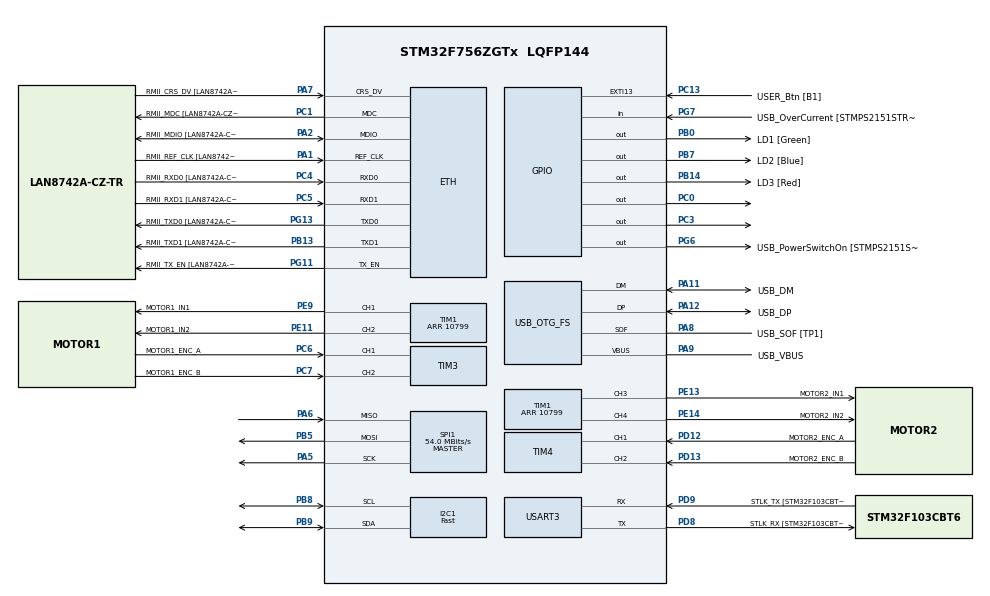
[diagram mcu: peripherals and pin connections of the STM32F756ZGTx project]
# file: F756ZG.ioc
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Dma.I2C1_RX.0.Direction=DMA_PERIPH_TO_MEMORY
Dma.I2C1_RX.0.FIFOMode=DMA_FIFOMODE_DISABLE
Dma.I2C1_RX.0.Instance=DMA1_Stream0
Dma.I2C1_RX.0.MemDataAlignment=DMA_MDATAALIGN_BYTE
Dma.I2C1_RX.0.MemInc=DMA_MINC_ENABLE
Dma.I2C1_RX.0.Mode=DMA_CIRCULAR
Dma.I2C1_RX.0.PeriphDataAlignment=DMA_PDATAALIGN_BYTE
Dma.I2C1_RX.0.PeriphInc=DMA_PINC_DISABLE
Dma.I2C1_RX.0.Priority=DMA_PRIORITY_LOW
Dma.I2C1_TX.1.Direction=DMA_MEMORY_TO_PERIPH
Dma.I2C1_TX.1.FIFOMode=DMA_FIFOMODE_DISABLE
Dma.I2C1_TX.1.Instance=DMA1_Stream6
Dma.I2C1_TX.1.MemDataAlignment=DMA_MDATAALIGN_BYTE
Dma.I2C1_TX.1.MemInc=DMA_MINC_ENABLE
Dma.I2C1_TX.1.Mode=DMA_CIRCULAR
Dma.I2C1_TX.1.PeriphDataAlignment=DMA_PDATAALIGN_BYTE
Dma.I2C1_TX.1.PeriphInc=DMA_PINC_DISABLE
Dma.I2C1_TX.1.Priority=DMA_PRIORITY_LOW
Dma.Request0=I2C1_RX
Dma.Request1=I2C1_TX
ETH.MediaInterface=HAL_ETH_RMII_MODE
ETH.PHY_Name=LAN8742A_PHY_ADDRESS
ETH.PHY_Value=0
ETH.PhyAddress=0
I2C1.Analog_Filter=I2C_ANALOGFILTER_ENABLE
I2C1.I2C_Rise_Time=0
I2C1.I2C_Speed_Mode=I2C_Fast
I2C1.Timing=0x6000030D
Mcu.Family=STM32F7
Mcu.Name=STM32F756ZGTx
Mcu.Package=LQFP144
NVIC.DMA1_Stream0_IRQn=true\:0\:0\:false\:false\:true\:false\:true\:true
NVIC.DMA1_Stream6_IRQn=true\:0\:0\:false\:false\:true\:false\:true\:true
NVIC.I2C1_ER_IRQn=true\:0\:0\:false\:false\:true\:true\:true\:true
NVIC.I2C1_EV_IRQn=true\:0\:0\:false\:false\:true\:true\:true\:true
NVIC.PriorityGroup=NVIC_PRIORITYGROUP_4
PA1.GPIO_Label=RMII_REF_CLK [LAN8742A-CZ-TR_REFCLK0]
PA1.Mode=RMII
PA1.Signal=ETH_REF_CLK
PA10.GPIO_Label=USB_ID
PA10.Signal=USB_OTG_FS_ID
PA11.GPIO_Label=USB_DM
PA11.Mode=Device_Only
PA11.Signal=USB_OTG_FS_DM
PA12.GPIO_Label=USB_DP
PA12.Mode=Device_Only
PA12.Signal=USB_OTG_FS_DP
PA13.GPIO_Label=TMS
PA13.Mode=Serial_Wire
PA13.Signal=SYS_JTMS-SWDIO
PA14.GPIO_Label=TCK
PA14.Mode=Serial_Wire
PA14.Signal=SYS_JTCK-SWCLK
PA2.GPIO_Label=RMII_MDIO [LAN8742A-CZ-TR_MDIO]
PA2.Mode=RMII
PA2.Signal=ETH_MDIO
PA5.Mode=Full_Duplex_Master
PA5.Signal=SPI1_SCK
PA6.Mode=Full_Duplex_Master
PA6.Signal=SPI1_MISO
PA7.GPIO_Label=RMII_CRS_DV [LAN8742A-CZ-TR_CRS_DV]
PA7.Mode=RMII
PA7.Signal=ETH_CRS_DV
PA8.GPIO_Label=USB_SOF [TP1]
PA8.Mode=Activate_SOF_FS
PA8.Signal=USB_OTG_FS_SOF
PA9.GPIO_Label=USB_VBUS
PA9.Mode=Activate_VBUS
PA9.Signal=USB_OTG_FS_VBUS
PB0.GPIO_Label=LD1 [Green]
PB0.Signal=GPIO_Output
PB13.GPIO_Label=RMII_TXD1 [LAN8742A-CZ-TR_TXD1]
PB13.Mode=RMII
PB13.Signal=ETH_TXD1
PB14.GPIO_Label=LD3 [Red]
PB14.Signal=GPIO_Output
PB3.GPIO_Label=SW0
PB3.Signal=SYS_JTDO-SWO
PB5.Mode=Full_Duplex_Master
PB5.Signal=SPI1_MOSI
PB7.GPIO_Label=LD2 [Blue]
PB7.Signal=GPIO_Output
PB8.GPIO_Pu=GPIO_PULLUP
PB8.Mode=I2C
PB8.Signal=I2C1_SCL
PB9.GPIO_Pu=GPIO_PULLUP
PB9.Mode=I2C
PB9.Signal=I2C1_SDA
PC0.Signal=GPIO_Output
PC1.GPIO_Label=RMII_MDC [LAN8742A-CZ-TR_MDC]
PC1.Mode=RMII
PC1.Signal=ETH_MDC
PC13.GPIO_Label=USER_Btn [B1]
PC13.Signal=GPXTI13
PC14/OSC32_IN.Mode=LSE-External-Oscillator
PC14/OSC32_IN.Signal=RCC_OSC32_IN
PC15/OSC32_OUT.Mode=LSE-External-Oscillator
PC15/OSC32_OUT.Signal=RCC_OSC32_OUT
PC3.Signal=GPIO_Output
PC4.GPIO_Label=RMII_RXD0 [LAN8742A-CZ-TR_RXD0]
PC4.Mode=RMII
PC4.Signal=ETH_RXD0
PC5.GPIO_Label=RMII_RXD1 [LAN8742A-CZ-TR_RXD1]
PC5.Mode=RMII
PC5.Signal=ETH_RXD1
PC6.GPIO_Label=MOTOR1_ENC_A
PC6.Signal=S_TIM3_CH1
PC7.GPIO_Label=MOTOR1_ENC_B
PC7.Signal=S_TIM3_CH2
PD12.GPIO_Label=MOTOR2_ENC_A
PD12.Signal=S_TIM4_CH1
PD13.GPIO_Label=MOTOR2_ENC_B
PD13.Signal=S_TIM4_CH2
PD8.GPIO_Label=STLK_RX [STM32F103CBT6_PA3]
PD8.Mode=Asynchronous
PD8.Signal=USART3_TX
PD9.GPIO_Label=STLK_TX [STM32F103CBT6_PA2]
PD9.Mode=Asynchronous
PD9.Signal=USART3_RX
PE11.GPIO_Label=MOTOR1_IN2
PE11.Signal=S_TIM1_CH2
PE13.GPIO_Label=MOTOR2_IN1
PE13.Signal=S_TIM1_CH3
PE14.GPIO_Label=MOTOR2_IN2
PE14.Signal=S_TIM1_CH4
PE5.GPIO_Label=PWM_MOTOR1
PE5.Signal=S_TIM9_CH1
PE6.GPIO_Label=PWM_MOTOR2
PE6.Signal=S_TIM9_CH2
PE9.GPIO_Label=MOTOR1_IN1
PE9.Signal=S_TIM1_CH1
PG11.GPIO_Label=RMII_TX_EN [LAN8742A-CZ-TR_TXEN]
PG11.Mode=RMII
PG11.Signal=ETH_TX_EN
PG13.GPIO_Label=RMII_TXD0 [LAN8742A-CZ-TR_TXD0]
PG13.Mode=RMII
PG13.Signal=ETH_TXD0
PG6.GPIO_Label=USB_PowerSwitchOn [STMPS2151STR_EN]
PG6.Signal=GPIO_Output
PG7.GPIO_Label=USB_OverCurrent [STMPS2151STR_FAULT]
PG7.Signal=GPIO_Input
PH0/OSC_IN.GPIO_Label=MCO [STM32F103CBT6_PA8]
PH0/OSC_IN.Mode=HSE-External-Clock-Source
PH0/OSC_IN.Signal=RCC_OSC_IN
PH1/OSC_OUT.Mode=HSE-External-Clock-Source
PH1/OSC_OUT.Signal=RCC_OSC_OUT
ProjectManager.HeapSize=0x200
ProjectManager.StackSize=0x400
ProjectManager.TargetToolchain=CMake
RCC.48MHZClocksFreq_Value=24000000
RCC.AHBFreq_Value=216000000
RCC.APB1Freq_Value=54000000
RCC.APB1TimCLKDivider=2
RCC.APB1TimFreq_Value=108000000
RCC.APB2CLKDivider=RCC_HCLK_DIV2
RCC.APB2Freq_Value=108000000
RCC.APB2TimFreq_Value=216000000
RCC.CortexFreq_Value=216000000
RCC.HCLKFreq_Value=216000000
RCC.HSE_VALUE=8000000
RCC.HSI_VALUE=16000000
RCC.PLLM=4
RCC.PLLMUL=RCC_PLL_MUL9
RCC.PLLN=216
RCC.PLLQ=9
RCC.PRESCALERUSB=RCC_USBCLKSOURCE_PLL_DIV1_5
RCC.SYSCLKFreq_VALUE=216000000
RCC.SYSCLKSource=RCC_SYSCLKSOURCE_PLLCLK
RCC.SYSCLKSourceVirtual=RCC_SYSCLKSOURCE_PLLCLK
RCC.USBFreq_Value=48000000
RCC.VCOOutputFreq_Value=432000000
SH.S_TIM1_CH1.0=TIM1_CH1,PWM Generation1 CH1
SH.S_TIM1_CH2.0=TIM1_CH2,PWM Generation2 CH2
SH.S_TIM1_CH3.0=TIM1_CH3,PWM Generation3 CH3
SH.S_TIM1_CH4.0=TIM1_CH4,PWM Generation4 CH4
SH.S_TIM3_CH1.0=TIM3_CH1,Encoder_Interface
SH.S_TIM3_CH2.0=TIM3_CH2,Encoder_Interface
SH.S_TIM4_CH1.0=TIM4_CH1,Encoder_Interface
SH.S_TIM4_CH2.0=TIM4_CH2,Encoder_Interface
SH.S_TIM9_CH1.0=TIM9_CH1
SH.S_TIM9_CH2.0=TIM9_CH2
SPI1.BaudRatePrescaler=SPI_BAUDRATEPRESCALER_2
SPI1.CalculateBaudRate=54.0 MBits/s
SPI1.Direction=SPI_DIRECTION_2LINES
SPI1.Mode=SPI_MODE_MASTER
SPI1.VirtualType=VM_MASTER
TIM1.Channel-PWM\ Generation1\ CH1=TIM_CHANNEL_1
TIM1.Channel-PWM\ Generation2\ CH2=TIM_CHANNEL_2
TIM1.Channel-PWM\ Generation3\ CH3=TIM_CHANNEL_3
TIM1.Channel-PWM\ Generation4\ CH4=TIM_CHANNEL_4
TIM1.Period=10799
USART3.VirtualMode-Asynchronous=VM_ASYNC
USB_OTG_FS.VirtualMode=Device_Only
board=NUCLEO-F756ZG

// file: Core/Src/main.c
/* USER CODE BEGIN Header */
/**
 ******************************************************************************
 * @file           : main.c
 * @brief          : Main program body
 ******************************************************************************
 * @attention
 *
 * Copyright (c) 2026 STMicroelectronics.
 * All rights reserved.
 *
 * This software is licensed under terms that can be found in the LICENSE file
 * in the root directory of this software component.
 * If no LICENSE file comes with this software, it is provided AS-IS.
 *
 ******************************************************************************
 */
/* USER CODE END Header */
#include "main.h"
#include "dma.h"
#include "eth.h"
#include "i2c.h"
#include "spi.h"
#include "tim.h"
#include "usart.h"
#include "usb_otg.h"
#include "gpio.h"

/* USER CODE BEGIN Includes */
#include "stdio.h"
#include "stdint.h"
#include "../../App/app.hpp"
/* USER CODE END Includes */

/* USER CODE BEGIN PD */
void i2cScaner();
/* USER CODE END PD */

/* USER CODE BEGIN PV */
extern UART_HandleTypeDef huart3;
extern I2C_HandleTypeDef hi2c1;

float accX = 0.0f;
float accY = 0.0f;
float accZ = 0.0f;
float gyrX = 0.0f;
float gyrY = 0.0f;
float gyrZ = 0.0f;
float angle = 0.0f;
float output = 0.0f;
/* USER CODE END PV */

void SystemClock_Config(void);

int main(void)
{

	/* MCU Configuration--------------------------------------------------------*/

	/* Reset of all peripherals, Initializes the Flash interface and the Systick. */
	HAL_Init();

	/* Configure the system clock */
	SystemClock_Config();

	/* Initialize all configured peripherals */
	MX_GPIO_Init();
	MX_DMA_Init();
	MX_ETH_Init();
	MX_I2C1_Init();
	MX_USART3_UART_Init();
	MX_USB_OTG_FS_PCD_Init();
	MX_SPI1_Init();
	MX_TIM1_Init();
	MX_TIM3_Init();
	MX_TIM4_Init();
	/* USER CODE BEGIN 2 */
	uint8_t reslt = appInit();
	//	if (!reslt) {
	//		printf("init was successful");
	//	} else {
	//		printf("init wasn't successful");
	//	}
	//	i2cScaner();
	/* USER CODE END 2 */

	/* Infinite loop */
	/* USER CODE BEGIN WHILE */
	while (1)
	{
		appRun(&accX, &accY, &accZ, &gyrX, &gyrY, &gyrZ, &angle, &output);
		if (reslt) {
			HAL_GPIO_TogglePin(GPIOC, GPIO_PIN_0);
		} else {
			HAL_GPIO_TogglePin(GPIOC, GPIO_PIN_3);
		}
		//		printf("Acc x - %f, y - %f, z - %f\n", accX, accY, accZ);
		//		printf("Gyr x - %f, y - %f, z - %f\n", gyrX, gyrY, gyrZ);
		//		printf("Angle on X - %f\n", angle);
		printf("%f,%f\n", output, angle);
		//		HAL_Delay(1000);
		/* USER CODE END WHILE */

	}
}

void SystemClock_Config(void)
{
	RCC_OscInitTypeDef RCC_OscInitStruct = {0};
	RCC_ClkInitTypeDef RCC_ClkInitStruct = {0};

	/** Configure LSE Drive Capability
	 */
	HAL_PWR_EnableBkUpAccess();

	/** Configure the main internal regulator output voltage
	 */
	__HAL_RCC_PWR_CLK_ENABLE();
	__HAL_PWR_VOLTAGESCALING_CONFIG(PWR_REGULATOR_VOLTAGE_SCALE1);

	/** Initializes the RCC Oscillators according to the specified parameters
	 * in the RCC_OscInitTypeDef structure.
	 */
	RCC_OscInitStruct.OscillatorType = RCC_OSCILLATORTYPE_HSE;
	RCC_OscInitStruct.HSEState = RCC_HSE_BYPASS;
	RCC_OscInitStruct.PLL.PLLState = RCC_PLL_ON;
	RCC_OscInitStruct.PLL.PLLSource = RCC_PLLSOURCE_HSE;
	RCC_OscInitStruct.PLL.PLLM = 4;
	RCC_OscInitStruct.PLL.PLLN = 216;
	RCC_OscInitStruct.PLL.PLLP = RCC_PLLP_DIV2;
	RCC_OscInitStruct.PLL.PLLQ = 9;
	if (HAL_RCC_OscConfig(&RCC_OscInitStruct) != HAL_OK)
	{
		Error_Handler();
	}

	/** Activate the Over-Drive mode
	 */
	if (HAL_PWREx_EnableOverDrive() != HAL_OK)
	{
		Error_Handler();
	}

	/** Initializes the CPU, AHB and APB buses clocks
	 */
	RCC_ClkInitStruct.ClockType = RCC_CLOCKTYPE_HCLK|RCC_CLOCKTYPE_SYSCLK
			|RCC_CLOCKTYPE_PCLK1|RCC_CLOCKTYPE_PCLK2;
	RCC_ClkInitStruct.SYSCLKSource = RCC_SYSCLKSOURCE_PLLCLK;
	RCC_ClkInitStruct.AHBCLKDivider = RCC_SYSCLK_DIV1;
	RCC_ClkInitStruct.APB1CLKDivider = RCC_HCLK_DIV1;
	RCC_ClkInitStruct.APB2CLKDivider = RCC_HCLK_DIV2;

	if (HAL_RCC_ClockConfig(&RCC_ClkInitStruct, FLASH_LATENCY_7) != HAL_OK)
	{
		Error_Handler();
	}
}

/* USER CODE BEGIN 4 */
void i2cScaner() {
	uint8_t chip_id = 0;
	for (uint8_t i = 1; i < 128; ++i) {
		if (HAL_I2C_Mem_Read(&hi2c1, (i << 1), 0x00, I2C_MEMADD_SIZE_8BIT, &chip_id, 1, 1000) == HAL_OK) {
			printf("address found: 0x%02X, chip_id: 0x%02X\n", i, chip_id);
		} else {
			printf("skip\n");
		}
	}
}

int __io_putchar(int ch) {
	HAL_UART_Transmit(&huart3, (uint8_t *)&ch, 1, 0xFFFF);

	return ch;
}
/* USER CODE END 4 */

void Error_Handler(void)
{
	__disable_irq();
	while (1)
	{
	}
}
